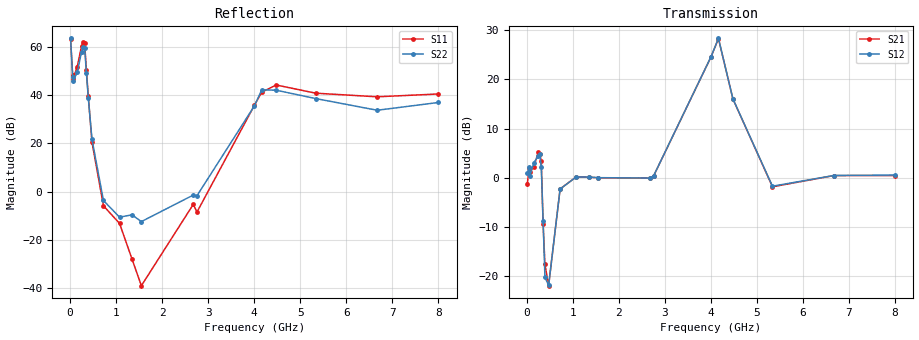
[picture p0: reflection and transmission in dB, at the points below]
!Agilent Technologies,N5230A,US43500312,A.07.50.67
!Agilent N5230A: A.07.50.67
!Date: Tuesday, June 09, 2015 15:39:13
!Correction: S11(Full 2 Port(1,2))
!S21(Full 2 Port(1,2))
!S12(Full 2 Port(1,2))
!S22(Full 2 Port(1,2))
!S2P File: Measurements: S11, S21, S12, S22:
# Hz S  MA  R 50
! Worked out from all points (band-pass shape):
!   1601 points, 10 MHz to 8 GHz, reference 50 ohm
!   highest |S21| = 28.30 dB at 4.165 GHz (marker M1); lowest = -22.0 dB at 474.4 MHz (marker M2)
!   |S21| within 3 dB of the highest: 4.027 GHz to 4.292 GHz (265.4 MHz wide, 6.38 % of centre)
!   lowest |S11| = -39.1 dB at 1.548 GHz (marker M3), VSWR 1.02, Z = 48.9 + j0.208 ohm
!   |S11| at or under -10 dB: 901.8 MHz to 2.182 GHz (1.28 GHz wide, 83 % of centre); 2.777 GHz to 2.949 GHz (171.6 MHz wide, 5.99 % of centre)
!   |S22| runs from -13.7 to 63.6 dB; largest |S21 - S12| = 1.1
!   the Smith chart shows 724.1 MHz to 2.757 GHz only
!   S11 on the Smith chart (normalised r, x): 724.1 MHz: 0.34, -0.19; 1.074 GHz: 1.41, +0.34; 2.757 GHz: 0.80, -0.70
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1e7  1491 171.1  0.8675 -66.6  1.116 0.5  1520 -19.4
5.494375e7  262.4 326.0  1.245 0.9  1.296 4.6  241.9 93.8
6.493125e7  221.8 337.4  1.134 7.8  1.053 5.1  196.2 97.8
1.548188e8  393.3 398.8  1.29 3.9  1.421 4.5  299.4 120.8
2.497e8  1062 405.9  1.827 3.5  1.67 1.0  805.9 119.6
2.796625e8  1273 418.4  1.739 29.5  1.76 25.5  986.8 133.2
3.146188e8  1217 444.5  1.494 61.2  1.299 56.8  981.9 162.4
3.545688e8  330 469.0  0.3387 87.6  0.3626 84.3  284.3 194.0
3.945188e8  96.03 471.7  0.1314 72.1  0.09694 68.8  89.94 207.0
4.744188e8  10.8 478.8  0.07988 71.3  0.08048 71.2  12.31 246.5
7.241062e8  0.5075 563.6  0.7699 145.5  0.7681 145.6  0.6543 436.4
1.073669e9  0.2187 751.2  1.019 109.1  1.017 109.0  0.2947 657.7
1.343331e9  0.04023 706.0  1.016 114.2  1.017 114.2  0.33 765.6
1.548075e9  0.01114 529.0  0.9992 114.7  1.002 114.6  0.2387 855.9
2.676662e9  0.5435 272.6  0.9901 119.5  0.9933 119.5  0.8484 1223.3
2.756562e9  0.3765 274.9  1.045 120.5  1.047 120.5  0.8219 1242.1
4.005e9  61.97 353.6  17.02 144.9  17.06 145.0  60.44 1530.8
4.1648e9  116.4 325.3  26.01 74.1  26.14 74.4  130 1496.1
4.479406e9  163.5 283.7  6.32 -44.6  6.332 -44.5  127.3 1437.6
5.338331e9  110.5 272.5  0.8095 18.3  0.8206 18.8  85.47 1413.3
6.671662e9  93.07 298.5  1.052 16.8  1.054 16.9  48.92 1354.3
8e9  106.4 317.9  1.054 11.6  1.065 11.8  70.85 1316.6
